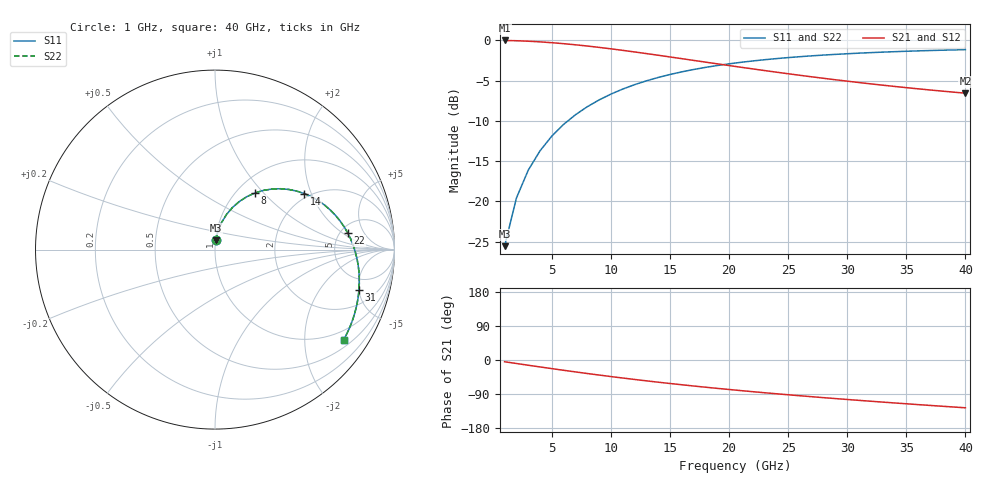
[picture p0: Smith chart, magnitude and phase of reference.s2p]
! circuitRF F0 spike reference -- case A, openEMS, PEC wire of true radius 12.7 um, dw 12.7 um
! openEMS probes -> S by postproc.py (own time column per probe); port 1 excited only;
! S22 = S11 and S12 = S21 by the mirror symmetry of the geometry (not a second run)
# GHz S RI R 50
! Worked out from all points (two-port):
!   40 points, 1 GHz to 40 GHz, reference 50 ohm
!   highest |S21| = -0.01 dB at 1 GHz (marker M1); lowest = -6.6 dB at 40 GHz (marker M2)
!   |S21| within 3 dB of the highest: start of sweep to 19.44 GHz
!   lowest |S11| = -25.6 dB at 1 GHz (marker M3), VSWR 1.11, Z = 50.1 + j5.27 ohm
!   |S11| at or under -10 dB: start of sweep to 6.365 GHz
!   |S22| runs from -25.6 to -1.2 dB; largest |S21 - S12| = 0
!   S11 on the Smith chart (normalised r, x): 1 GHz: 1.00, +0.11; 8 GHz: 1.21, +0.90; 14 GHz: 1.88, +1.79; 22 GHz: 5.78, +2.43; 31 GHz: 3.46, -5.02; 40 GHz: 0.70, -3.02
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1  0.00421 0.0524  0.9953 -0.0805  0.9953 -0.0805  0.00421 0.0524
2  0.0166 0.1034  0.9816 -0.1595  0.9816 -0.1595  0.0166 0.1034
3  0.0369 0.1516  0.9592 -0.2356  0.9592 -0.2356  0.0369 0.1516
4  0.0641 0.1958  0.9289 -0.3076  0.9289 -0.3076  0.0641 0.1958
5  0.0975 0.2349  0.8917 -0.3744  0.8917 -0.3744  0.0975 0.2349
6  0.136 0.2683  0.8485 -0.4352  0.8485 -0.4352  0.136 0.2683
7  0.1784 0.2953  0.8007 -0.4895  0.8007 -0.4895  0.1784 0.2953
8  0.2235 0.3159  0.7493 -0.5371  0.7493 -0.5371  0.2235 0.3159
9  0.2703 0.3299  0.6955 -0.5779  0.6955 -0.5779  0.2703 0.3299
11  0.365 0.3391  0.5846 -0.6398  0.5846 -0.6398  0.365 0.3391
12  0.4112 0.335  0.5291 -0.6616  0.5291 -0.6616  0.4112 0.335
14  0.4985 0.3119  0.4214 -0.6894  0.4214 -0.6894  0.4985 0.3119
16  0.5762 0.2724  0.3208 -0.6994  0.3208 -0.6994  0.5762 0.2724
18  0.6424 0.2206  0.229 -0.6957  0.229 -0.6957  0.6424 0.2206
21  0.7191 0.1275  0.1091 -0.6719  0.1091 -0.6719  0.7191 0.1275
22  0.7388 0.0938  0.0739 -0.6605  0.0739 -0.6605  0.7388 0.0938
24  0.7698 0.0242  0.00995 -0.6343  0.00995 -0.6343  0.7698 0.0242
27  0.797 -0.0825  -0.071 -0.5892  -0.071 -0.5892  0.797 -0.0825
31  0.8023 -0.2227  -0.1556 -0.5242  -0.1556 -0.5242  0.8023 -0.2227
34  0.7868 -0.3228  -0.205 -0.4749  -0.205 -0.4749  0.7868 -0.3228
37  0.7575 -0.4167  -0.2448 -0.4264  -0.2448 -0.4264  0.7575 -0.4167
40  0.7164 -0.5033  -0.2769 -0.3794  -0.2769 -0.3794  0.7164 -0.5033
